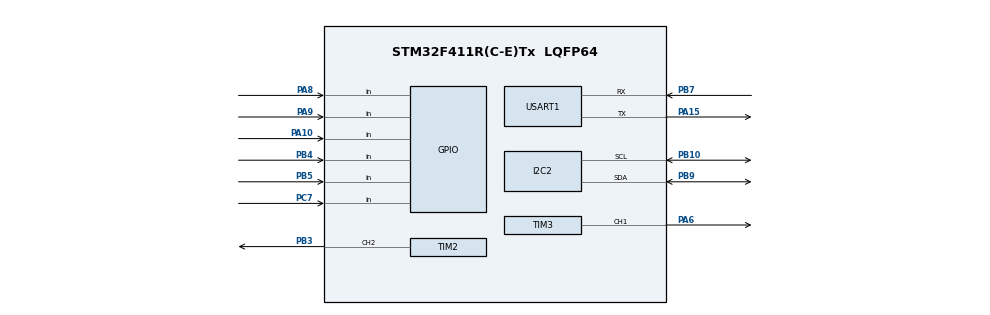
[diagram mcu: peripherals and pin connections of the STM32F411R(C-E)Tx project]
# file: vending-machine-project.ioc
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Mcu.Family=STM32F4
Mcu.Name=STM32F411R(C-E)Tx
Mcu.Package=LQFP64
NVIC.PriorityGroup=NVIC_PRIORITYGROUP_0
PA10.Signal=GPIO_Input
PA13.GPIO_Label=TMS
PA13.Mode=Serial_Wire
PA13.Signal=SYS_JTMS-SWDIO
PA14.GPIO_Label=TCK
PA14.Mode=Serial_Wire
PA14.Signal=SYS_JTCK-SWCLK
PA15.Mode=Asynchronous
PA15.Signal=USART1_TX
PA3.GPIO_Label=USART_RX
PA3.Signal=USART2_RX
PA6.Signal=S_TIM3_CH1
PA8.Signal=GPIO_Input
PA9.Signal=GPIO_Input
PB10.Mode=I2C
PB10.Signal=I2C2_SCL
PB3.Signal=S_TIM2_CH2
PB4.Signal=GPIO_Input
PB5.Signal=GPIO_Input
PB7.Mode=Asynchronous
PB7.Signal=USART1_RX
PB9.Mode=I2C
PB9.Signal=I2C2_SDA
PC14-OSC32_IN.Mode=LSE-External-Oscillator
PC14-OSC32_IN.Signal=RCC_OSC32_IN
PC15-OSC32_OUT.Mode=LSE-External-Oscillator
PC15-OSC32_OUT.Signal=RCC_OSC32_OUT
PC7.Signal=GPIO_Input
PH0\ -\ OSC_IN.Mode=HSE-External-Clock-Source
PH0\ -\ OSC_IN.Signal=RCC_OSC_IN
PH1\ -\ OSC_OUT.Mode=HSE-External-Clock-Source
PH1\ -\ OSC_OUT.Signal=RCC_OSC_OUT
ProjectManager.HeapSize=0x200
ProjectManager.StackSize=0x400
ProjectManager.TargetToolchain=STM32CubeIDE
RCC.48MHZClocksFreq_Value=36000000
RCC.AHBFreq_Value=72000000
RCC.APB1CLKDivider=RCC_HCLK_DIV2
RCC.APB1Freq_Value=36000000
RCC.APB1TimFreq_Value=72000000
RCC.APB2Freq_Value=72000000
RCC.APB2TimFreq_Value=72000000
RCC.CortexFreq_Value=72000000
RCC.FLatency-AdvancedSettings=FLASH_LATENCY_2
RCC.HCLKFreq_Value=72000000
RCC.HSE_VALUE=8000000
RCC.HSI_VALUE=16000000
RCC.PLLM=8
RCC.PLLN=72
RCC.SYSCLKFreq_VALUE=72000000
RCC.SYSCLKSource=RCC_SYSCLKSOURCE_PLLCLK
RCC.VCOOutputFreq_Value=144000000
SH.S_TIM2_CH2.0=TIM2_CH2,PWM Generation2 CH2
SH.S_TIM3_CH1.0=TIM3_CH1,PWM Generation1 CH1
TIM2.Channel-PWM\ Generation2\ CH2=TIM_CHANNEL_2
TIM2.Period=65535
TIM2.Prescaler=72-1
TIM3.Channel-PWM\ Generation1\ CH1=TIM_CHANNEL_1
TIM3.Prescaler=72-1
USART1.VirtualMode=VM_ASYNC
VP_TIM2_VS_ClockSourceINT.Mode=Internal
board=NUCLEO-F411RE

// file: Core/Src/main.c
/* USER CODE BEGIN Header */
/**
  ******************************************************************************
  * @file           : main.c
  * @brief          : Main program body
  ******************************************************************************
  * @attention
  *
  * Copyright (c) 2024 STMicroelectronics.
  * All rights reserved.
  *
  * This software is licensed under terms that can be found in the LICENSE file
  * in the root directory of this software component.
  * If no LICENSE file comes with this software, it is provided AS-IS.
  *
  ******************************************************************************
  */
/* USER CODE END Header */
#include "main.h"

/* USER CODE BEGIN Includes */
#include "liquidcrystal_i2c.h"

/* USER CODE END Includes */

/* USER CODE BEGIN PD */
#define PRICE 3

/* USER CODE END PD */

I2C_HandleTypeDef hi2c2;

TIM_HandleTypeDef htim2;
TIM_HandleTypeDef htim3;

UART_HandleTypeDef huart1;

/* USER CODE BEGIN PV */

uint8_t item = 0;
uint8_t credit = 0;

/* USER CODE END PV */

void SystemClock_Config(void);
static void MX_GPIO_Init(void);
static void MX_TIM2_Init(void);
static void MX_I2C2_Init(void);
static void MX_TIM3_Init(void);
static void MX_USART1_UART_Init(void);
/* USER CODE BEGIN PFP */
static void Dispense_Item(void);
static void Dispense_Change(uint8_t amount);

/* USER CODE END PFP */

int main(void)
{

  /* MCU Configuration--------------------------------------------------------*/

  /* Reset of all peripherals, Initializes the Flash interface and the Systick. */
  HAL_Init();

  /* USER CODE BEGIN Init */
  HD44780_Init(2);

  /* USER CODE END Init */

  /* Configure the system clock */
  SystemClock_Config();

  /* Initialize all configured peripherals */
  MX_GPIO_Init();
  MX_TIM2_Init();
  MX_I2C2_Init();
  MX_TIM3_Init();
  MX_USART1_UART_Init();
  /* USER CODE BEGIN 2 */
  HAL_TIM_PWM_Start(&htim2, TIM_CHANNEL_2);
  HAL_TIM_PWM_Start(&htim3, TIM_CHANNEL_1);

  /* USER CODE END 2 */

  /* Infinite loop */
  while (1)
  {

    /* USER CODE BEGIN 3 */

	  if (HAL_GPIO_ReadPin(GPIOA, GPIO_PIN_10))
	  {
		  item = 1;
		  printf("Item selected: %d\n", item);
		  HAL_Delay(500);
	  }

	  if (HAL_GPIO_ReadPin(GPIOB, GPIO_PIN_5))
	  {
		  credit += 1;
		  printf("Credit %dKM added. Total: %d", 1, credit);
		  HAL_Delay(500);
	  }

	  /*if (HAL_GPIO_ReadPin(GPIOB, GPIO_PIN_4))
	  {
		  credit += 2;
		  printf("Credit %dKM added. Total: %d", 2, credit);
		  HAL_Delay(500);
	  }*/

	  if (HAL_GPIO_ReadPin(GPIOA, GPIO_PIN_8))
	  {
		  credit += 5;
		  printf("Credit %dKM added. Total: %d", 5, credit);
		  HAL_Delay(500);
	  }

	  /*if (HAL_GPIO_ReadPin(GPIOA, GPIO_PIN_9))
	  {
		  credit += 10;
		  printf("Credit %dKM added. Total: %d", 10, credit);
		  HAL_Delay(500);
	  }*/

	  /*if (HAL_GPIO_ReadPin(GPIOC, GPIO_PIN_7))
	  {
		  credit += 20;
		  printf("Credit %dKM added. Total: %d", 20, credit);
		  HAL_Delay(500);
	  }*/

	  if (item && credit >= PRICE)
	  {
		  printf("Dispensing item: %d", item);
		  Dispense_Item();

		  uint8_t change = credit - PRICE;
		  printf("Dispensing change: %d", change);
		  if (change > 0)
		  {
			  Dispense_Change(change);
		  }

		  item = 0;
		  credit = 0;
	  }
  }
  /* USER CODE END 3 */
}

void SystemClock_Config(void)
{
  RCC_OscInitTypeDef RCC_OscInitStruct = {0};
  RCC_ClkInitTypeDef RCC_ClkInitStruct = {0};

  /** Configure the main internal regulator output voltage
  */
  __HAL_RCC_PWR_CLK_ENABLE();
  __HAL_PWR_VOLTAGESCALING_CONFIG(PWR_REGULATOR_VOLTAGE_SCALE1);

  /** Initializes the RCC Oscillators according to the specified parameters
  * in the RCC_OscInitTypeDef structure.
  */
  RCC_OscInitStruct.OscillatorType = RCC_OSCILLATORTYPE_HSE;
  RCC_OscInitStruct.HSEState = RCC_HSE_BYPASS;
  RCC_OscInitStruct.PLL.PLLState = RCC_PLL_ON;
  RCC_OscInitStruct.PLL.PLLSource = RCC_PLLSOURCE_HSE;
  RCC_OscInitStruct.PLL.PLLM = 16;
  RCC_OscInitStruct.PLL.PLLN = 336;
  RCC_OscInitStruct.PLL.PLLP = RCC_PLLP_DIV4;
  RCC_OscInitStruct.PLL.PLLQ = 4;
  if (HAL_RCC_OscConfig(&RCC_OscInitStruct) != HAL_OK)
  {
    Error_Handler();
  }

  /** Initializes the CPU, AHB and APB buses clocks
  */
  RCC_ClkInitStruct.ClockType = RCC_CLOCKTYPE_HCLK|RCC_CLOCKTYPE_SYSCLK
                              |RCC_CLOCKTYPE_PCLK1|RCC_CLOCKTYPE_PCLK2;
  RCC_ClkInitStruct.SYSCLKSource = RCC_SYSCLKSOURCE_PLLCLK;
  RCC_ClkInitStruct.AHBCLKDivider = RCC_SYSCLK_DIV1;
  RCC_ClkInitStruct.APB1CLKDivider = RCC_HCLK_DIV2;
  RCC_ClkInitStruct.APB2CLKDivider = RCC_HCLK_DIV1;

  if (HAL_RCC_ClockConfig(&RCC_ClkInitStruct, FLASH_LATENCY_1) != HAL_OK)
  {
    Error_Handler();
  }
}

static void MX_I2C2_Init(void)
{

  hi2c2.Instance = I2C2;
  hi2c2.Init.ClockSpeed = 100000;
  hi2c2.Init.DutyCycle = I2C_DUTYCYCLE_2;
  hi2c2.Init.OwnAddress1 = 0;
  hi2c2.Init.AddressingMode = I2C_ADDRESSINGMODE_7BIT;
  hi2c2.Init.DualAddressMode = I2C_DUALADDRESS_DISABLE;
  hi2c2.Init.OwnAddress2 = 0;
  hi2c2.Init.GeneralCallMode = I2C_GENERALCALL_DISABLE;
  hi2c2.Init.NoStretchMode = I2C_NOSTRETCH_DISABLE;
  if (HAL_I2C_Init(&hi2c2) != HAL_OK)
  {
    Error_Handler();
  }

}

static void MX_TIM2_Init(void)
{

  TIM_ClockConfigTypeDef sClockSourceConfig = {0};
  TIM_MasterConfigTypeDef sMasterConfig = {0};
  TIM_OC_InitTypeDef sConfigOC = {0};

  htim2.Instance = TIM2;
  htim2.Init.Prescaler = 72-1;
  htim2.Init.CounterMode = TIM_COUNTERMODE_UP;
  htim2.Init.Period = 65535;
  htim2.Init.ClockDivision = TIM_CLOCKDIVISION_DIV1;
  htim2.Init.AutoReloadPreload = TIM_AUTORELOAD_PRELOAD_DISABLE;
  if (HAL_TIM_Base_Init(&htim2) != HAL_OK)
  {
    Error_Handler();
  }
  sClockSourceConfig.ClockSource = TIM_CLOCKSOURCE_INTERNAL;
  if (HAL_TIM_ConfigClockSource(&htim2, &sClockSourceConfig) != HAL_OK)
  {
    Error_Handler();
  }
  if (HAL_TIM_PWM_Init(&htim2) != HAL_OK)
  {
    Error_Handler();
  }
  sMasterConfig.MasterOutputTrigger = TIM_TRGO_RESET;
  sMasterConfig.MasterSlaveMode = TIM_MASTERSLAVEMODE_DISABLE;
  if (HAL_TIMEx_MasterConfigSynchronization(&htim2, &sMasterConfig) != HAL_OK)
  {
    Error_Handler();
  }
  sConfigOC.OCMode = TIM_OCMODE_PWM1;
  sConfigOC.Pulse = 0;
  sConfigOC.OCPolarity = TIM_OCPOLARITY_HIGH;
  sConfigOC.OCFastMode = TIM_OCFAST_DISABLE;
  if (HAL_TIM_PWM_ConfigChannel(&htim2, &sConfigOC, TIM_CHANNEL_2) != HAL_OK)
  {
    Error_Handler();
  }
  HAL_TIM_MspPostInit(&htim2);

}

static void MX_TIM3_Init(void)
{

  TIM_MasterConfigTypeDef sMasterConfig = {0};
  TIM_OC_InitTypeDef sConfigOC = {0};

  htim3.Instance = TIM3;
  htim3.Init.Prescaler = 72-1;
  htim3.Init.CounterMode = TIM_COUNTERMODE_UP;
  htim3.Init.Period = 65535;
  htim3.Init.ClockDivision = TIM_CLOCKDIVISION_DIV1;
  htim3.Init.AutoReloadPreload = TIM_AUTORELOAD_PRELOAD_DISABLE;
  if (HAL_TIM_PWM_Init(&htim3) != HAL_OK)
  {
    Error_Handler();
  }
  sMasterConfig.MasterOutputTrigger = TIM_TRGO_RESET;
  sMasterConfig.MasterSlaveMode = TIM_MASTERSLAVEMODE_DISABLE;
  if (HAL_TIMEx_MasterConfigSynchronization(&htim3, &sMasterConfig) != HAL_OK)
  {
    Error_Handler();
  }
  sConfigOC.OCMode = TIM_OCMODE_PWM1;
  sConfigOC.Pulse = 0;
  sConfigOC.OCPolarity = TIM_OCPOLARITY_HIGH;
  sConfigOC.OCFastMode = TIM_OCFAST_DISABLE;
  if (HAL_TIM_PWM_ConfigChannel(&htim3, &sConfigOC, TIM_CHANNEL_1) != HAL_OK)
  {
    Error_Handler();
  }
  HAL_TIM_MspPostInit(&htim3);

}

static void MX_USART1_UART_Init(void)
{

  huart1.Instance = USART1;
  huart1.Init.BaudRate = 115200;
  huart1.Init.WordLength = UART_WORDLENGTH_8B;
  huart1.Init.StopBits = UART_STOPBITS_1;
  huart1.Init.Parity = UART_PARITY_NONE;
  huart1.Init.Mode = UART_MODE_TX_RX;
  huart1.Init.HwFlowCtl = UART_HWCONTROL_NONE;
  huart1.Init.OverSampling = UART_OVERSAMPLING_16;
  if (HAL_UART_Init(&huart1) != HAL_OK)
  {
    Error_Handler();
  }

}

static void MX_GPIO_Init(void)
{
  GPIO_InitTypeDef GPIO_InitStruct = {0};

  /* GPIO Ports Clock Enable */
  __HAL_RCC_GPIOC_CLK_ENABLE();
  __HAL_RCC_GPIOH_CLK_ENABLE();
  __HAL_RCC_GPIOA_CLK_ENABLE();
  __HAL_RCC_GPIOB_CLK_ENABLE();

  /*Configure GPIO pin : USART_RX_Pin */
  GPIO_InitStruct.Pin = USART_RX_Pin;
  GPIO_InitStruct.Mode = GPIO_MODE_AF_PP;
  GPIO_InitStruct.Pull = GPIO_NOPULL;
  GPIO_InitStruct.Speed = GPIO_SPEED_FREQ_VERY_HIGH;
  GPIO_InitStruct.Alternate = GPIO_AF7_USART2;
  HAL_GPIO_Init(USART_RX_GPIO_Port, &GPIO_InitStruct);

  /*Configure GPIO pin : PC7 */
  GPIO_InitStruct.Pin = GPIO_PIN_7;
  GPIO_InitStruct.Mode = GPIO_MODE_INPUT;
  GPIO_InitStruct.Pull = GPIO_NOPULL;
  HAL_GPIO_Init(GPIOC, &GPIO_InitStruct);

  /*Configure GPIO pins : PA8 PA9 PA10 */
  GPIO_InitStruct.Pin = GPIO_PIN_8|GPIO_PIN_9|GPIO_PIN_10;
  GPIO_InitStruct.Mode = GPIO_MODE_INPUT;
  GPIO_InitStruct.Pull = GPIO_NOPULL;
  HAL_GPIO_Init(GPIOA, &GPIO_InitStruct);

  /*Configure GPIO pins : PB4 PB5 */
  GPIO_InitStruct.Pin = GPIO_PIN_4|GPIO_PIN_5;
  GPIO_InitStruct.Mode = GPIO_MODE_INPUT;
  GPIO_InitStruct.Pull = GPIO_NOPULL;
  HAL_GPIO_Init(GPIOB, &GPIO_InitStruct);

}

/* USER CODE BEGIN 4 */
void Dispense_Item(void)
{
	__HAL_TIM_SET_COMPARE(&htim2, TIM_CHANNEL_2, 500);
	HAL_Delay(1000);
	__HAL_TIM_SET_COMPARE(&htim2, TIM_CHANNEL_2, 1000);
	HAL_Delay(1000);
	__HAL_TIM_SET_COMPARE(&htim2, TIM_CHANNEL_2, 1500);
	HAL_Delay(1000);
	__HAL_TIM_SET_COMPARE(&htim2, TIM_CHANNEL_2, 0);
	HAL_Delay(500);
}

void Dispense_Change(uint8_t amount)
{
	for (uint8_t i = 0; i < amount; ++i)
	{
		__HAL_TIM_SET_COMPARE(&htim3, TIM_CHANNEL_1, 500);
		HAL_Delay(1000);
		__HAL_TIM_SET_COMPARE(&htim3, TIM_CHANNEL_1, 1000);
		HAL_Delay(1000);
		__HAL_TIM_SET_COMPARE(&htim3, TIM_CHANNEL_1, 0);
		HAL_Delay(500);
	}
}

/* USER CODE END 4 */

void Error_Handler(void)
{
  __disable_irq();
  while (1)
  {
  }
}
